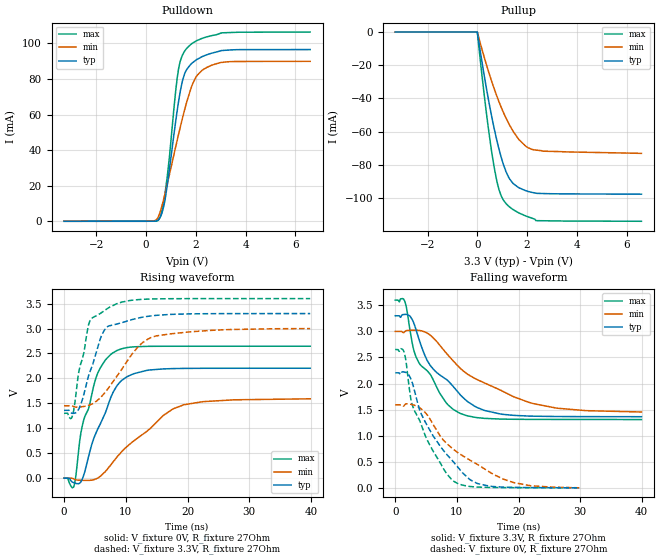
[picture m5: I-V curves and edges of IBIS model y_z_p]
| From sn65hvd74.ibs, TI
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|   y_z Model
[Model]   y_z_p
Model_type   Output
Polarity   Non-Inverting
Vmeas = 1.65
Vref = 1.956
Cref = 50pF
Rref = 27
|   typ   min   max
|   (nom PVT)   (fast PVT)   (slow PVT)
|Avergae
C_comp   1.391e-11   1.371e-11   1.548e-11
| Where nom  PVT is Nominal Process, 3.3V, 27C
|   Fast PVT is Strong Process,  3.6V, -40C
|   Slow PVT is Weak Process,   3V, 150C
[Voltage Range]   3.3   3   3.6
|Junction Temperature
[Temperature Range]   27   150   -40
[Pullup Reference]   3.3   3   3.6
[Pulldown Reference]   0   0   0
[Power Clamp Reference]   3.3   3   3.6
[GND Clamp Reference]   0   0   0
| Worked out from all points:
|   slope of the pulldown table from 0 to 0.495 V, typ, clamps not added: 584 ohm
|   slope of the pullup table from 0 to 0.495 V, typ, clamps not added: 11.1 ohm
|   falling waveform, V_fixture 3.3V, R_fixture 27Ohm: 20-80 % time 7.14ns typ, 11.4ns min, 5.25ns max; typ from 3.3 V to 1.36 V
|   rising waveform, V_fixture 0V, R_fixture 27Ohm: 20-80 % time 4.15ns typ, 8.36ns min, 3.15ns max; typ from 0 V to 2.2 V
|   rising waveform, V_fixture 3.3V, R_fixture 27Ohm: 20-80 % time 2.94ns typ, 5.55ns min, 2.14ns max; typ from 1.36 V to 3.3 V
|   falling waveform, V_fixture 0V, R_fixture 27Ohm: 20-80 % time 6.51ns typ, 9.22ns min, 4.98ns max; typ from 2.21 V to 0 V
[Pulldown]
|   Voltage   I(typ)   I(min)   I(max)
-3.3V     -6.612uA   -9.318uA   -6.374uA
336mV     41.43uA    229.2uA    18.75uA
519.6mV   1.175mA    3.381mA    1.076mA
670.8mV   6.19mA     10.37mA    7.974mA
847.2mV   19.71mA    20.58mA    24.58mA
1.207V    57.83mA    42.86mA    75.34mA
1.311V    67.7mA     49.13mA    85.95mA
1.541V    82.6mA     62.22mA    95.46mA
1.815V    88.49mA    75.13mA    99.61mA
2.253V    92.56mA    84.88mA    102.8mA
3.021V    95.98mA    89.33mA    105.9mA
6.6V      96.55mA    89.94mA    106.4mA
[Pullup]
|   Voltage   I(typ)   I(min)   I(max)
-3.3V     13.22uA    17.2uA     13.33uA
0V        0A         0A         0A
372mV     -34.39mA   -19.93mA   -49.55mA
672mV     -57.7mA    -33.86mA   -80.94mA
816mV     -67.2mA    -39.81mA   -91.73mA
955.2mV   -75.16mA   -45.09mA   -98.48mA
1.155V    -84.1mA    -51.84mA   -103.3mA
1.296V    -88.39mA   -56mA      -105.3mA
1.68V     -93.83mA   -64.82mA   -109mA
2.212V    -96.61mA   -70.72mA   -112.2mA
2.358V    -97mA      -71.09mA   -113.6mA
6.6V      -97.65mA   -73.05mA   -114mA
[Ramp]
R_load = 27
|   typ   min   max
dV/dt_r   1.3224/4.12948e-09   0.954711/8.31809e-09   1.58721/3.15212e-09
dV/dt_f   1.16141/7.1332e-09   0.927257/1.13811e-08   1.37377/5.21426e-09
[Falling Waveform]
V_fixture = 3.3V
V_fixture_min = 3V
V_fixture_max = 3.6V
R_fixture = 27Ohm
|   Time   V(typ)   V(min)   V(max)
0s        3.3V       3V         3.6V
1.55ns    3.325V     2.998V     3.576V
2.89ns    3.194V     3.023V     2.695V
3.83ns    2.857V     3.019V     2.402V
5.645ns   2.353V     2.931V     2.182V
8.245ns   2.082V     2.589V     1.635V
10.37ns   1.809V     2.312V     1.438V
14.48ns   1.484V     2.012V     1.333V
22.48ns   1.374V     1.613V     1.313V
39.95ns   1.364V     1.454V     1.31V
[Rising Waveform]
V_fixture = 0V
V_fixture_min = 0V
V_fixture_max = 0V
R_fixture = 27Ohm
|   Time   V(typ)   V(min)   V(max)
0s        11.3nV     106.8nV    12.29nV
1.57ns    -90.21mV   -13.88mV   -175.1mV
1.945ns   -105mV     -33.14mV   75.73mV
2.735ns   -72.71mV   -41.79mV   907.2mV
5.445ns   981.1mV    1.497mV    2.102V
6.75ns    1.329V     141mV      2.378V
8.525ns   1.846V     417.5mV    2.557V
11.37ns   2.097V     754.6mV    2.634V
19.39ns   2.201V     1.472V     2.645V
39.85ns   2.204V     1.591V     2.645V
[Rising Waveform]
V_fixture = 3.3V
V_fixture_min = 3V
V_fixture_max = 3.6V
R_fixture = 27Ohm
|   Time   V(typ)   V(min)   V(max)
0s        1.36V      1.452V     1.301V
1.395ns   1.3V       1.446V     1.26V
2.635ns   1.452V     1.429V     2.266V
3.185ns   1.669V     1.437V     2.498V
4.175ns   2.127V     1.468V     3.149V
6.555ns   2.972V     1.706V     3.36V
8.56ns    3.09V      2.043V     3.498V
11.89ns   3.207V     2.618V     3.578V
14.92ns   3.264V     2.852V     3.595V
39.85ns   3.3V       3V         3.6V
[Falling Waveform]
V_fixture = 0V
V_fixture_min = 0V
V_fixture_max = 0V
R_fixture = 27Ohm
|   Time   V(typ)   V(min)   V(max)
0s        2.206V     1.592V     2.652V
1.365ns   2.223V     1.569V     2.624V
2.215ns   2.16V      1.609V     1.967V
2.695ns   2.041V     1.598V     1.616V
5.2ns     1.192V     1.398V     913.7mV
9.46ns    495.8mV    735.9mV    127.8mV
12.23ns   150.3mV    525.1mV    24.73mV
15.38ns   30.72mV    297.4mV    7.547mV
21.96ns   4.958mV    40.46mV    2.357mV
29.85ns   493.2uV    901.7uV    380.4uV
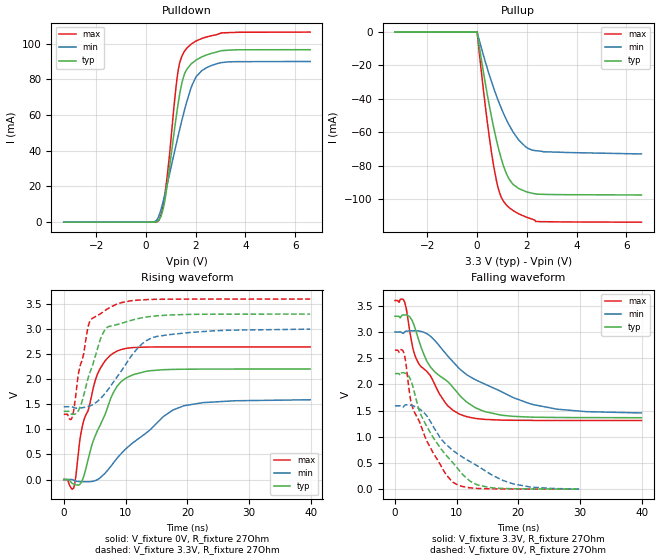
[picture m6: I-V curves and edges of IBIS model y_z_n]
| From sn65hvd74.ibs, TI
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[Model]   y_z_n
Model_type   Output
Polarity   Non-Inverting
Vmeas = 1.65
Vref = 1.956
Cref = 50pF
Rref = 27
|   typ   min   max
|   (nom PVT)   (fast PVT)   (slow PVT)
|Avergae
C_comp   1.391e-11   1.371e-11   1.548e-11
| Where nom  PVT is Nominal Process, 3.3V, 27C
|   Fast PVT is Strong Process,  3.6V, -40C
|   Slow PVT is Weak Process,   3V, 150C
[Voltage Range]   3.3   3   3.6
|Junction Temperature
[Temperature Range]   27   150   -40
[Pullup Reference]   3.3   3   3.6
[Pulldown Reference]   0   0   0
[Power Clamp Reference]   3.3   3   3.6
[GND Clamp Reference]   0   0   0
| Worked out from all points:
|   slope of the pulldown table from 0 to 0.495 V, typ, clamps not added: 584 ohm
|   slope of the pullup table from 0 to 0.495 V, typ, clamps not added: 11.1 ohm
|   falling waveform, V_fixture 3.3V, R_fixture 27Ohm: 20-80 % time 7.14ns typ, 11.4ns min, 5.25ns max; typ from 3.3 V to 1.36 V
|   rising waveform, V_fixture 0V, R_fixture 27Ohm: 20-80 % time 4.14ns typ, 8.35ns min, 3.14ns max; typ from 0 V to 2.2 V
|   rising waveform, V_fixture 3.3V, R_fixture 27Ohm: 20-80 % time 2.95ns typ, 5.55ns min, 2.15ns max; typ from 1.36 V to 3.3 V
|   falling waveform, V_fixture 0V, R_fixture 27Ohm: 20-80 % time 6.51ns typ, 9.22ns min, 4.99ns max; typ from 2.21 V to 0 V
[Pulldown]
|   Voltage   I(typ)   I(min)   I(max)
-3.3V     -6.612uA   -9.318uA   -6.374uA
336mV     41.43uA    229.2uA    18.75uA
519.6mV   1.175mA    3.381mA    1.076mA
670.8mV   6.19mA     10.37mA    7.974mA
847.2mV   19.71mA    20.58mA    24.58mA
1.207V    57.83mA    42.86mA    75.34mA
1.311V    67.7mA     49.13mA    85.95mA
1.541V    82.6mA     62.22mA    95.46mA
1.815V    88.49mA    75.13mA    99.61mA
2.253V    92.56mA    84.88mA    102.8mA
3.021V    95.98mA    89.33mA    105.9mA
6.6V      96.55mA    89.94mA    106.4mA
[Pullup]
|   Voltage   I(typ)   I(min)   I(max)
-3.3V     13.22uA    17.2uA     13.33uA
0V        0A         0A         0A
372mV     -34.39mA   -19.93mA   -49.55mA
672mV     -57.7mA    -33.86mA   -80.94mA
816mV     -67.2mA    -39.81mA   -91.73mA
955.2mV   -75.16mA   -45.09mA   -98.48mA
1.155V    -84.1mA    -51.84mA   -103.3mA
1.296V    -88.39mA   -56mA      -105.3mA
1.68V     -93.83mA   -64.82mA   -109mA
2.212V    -96.61mA   -70.72mA   -112.2mA
2.358V    -97mA      -71.09mA   -113.6mA
6.6V      -97.65mA   -73.05mA   -114mA
[Ramp]
R_load = 27
|   typ   min   max
dV/dt_r   1.32241/4.11811e-09   0.954711/8.31808e-09   1.58722/3.13788e-09
dV/dt_f   1.16141/7.13421e-09   0.927261/1.13804e-08   1.37378/5.21645e-09
[Falling Waveform]
V_fixture = 3.3V
V_fixture_min = 3V
V_fixture_max = 3.6V
R_fixture = 27Ohm
|   Time   V(typ)   V(min)   V(max)
0s        3.3V       3V         3.6V
1.545ns   3.325V     3V         3.576V
2.89ns    3.19V      3.023V     2.695V
3.82ns    2.857V     3.019V     2.403V
5.645ns   2.351V     2.929V     2.182V
8.245ns   2.081V     2.585V     1.635V
10.37ns   1.808V     2.309V     1.438V
14.47ns   1.484V     2.011V     1.333V
22.46ns   1.374V     1.613V     1.313V
39.95ns   1.364V     1.454V     1.31V
[Rising Waveform]
V_fixture = 0V
V_fixture_min = 0V
V_fixture_max = 0V
R_fixture = 27Ohm
|   Time   V(typ)   V(min)   V(max)
0s        11.3nV     106.8nV    12.29nV
1.59ns    -89.85mV   -10.67mV   -175.7mV
1.965ns   -104.7mV   -32.07mV   74.11mV
2.76ns    -74.24mV   -41.8mV    906.7mV
5.455ns   974.5mV    -1.406mV   2.102V
6.795ns   1.332V     139.6mV    2.384V
8.615ns   1.858V     422.4mV    2.562V
11.38ns   2.097V     750.4mV    2.634V
19.43ns   2.201V     1.471V     2.645V
39.85ns   2.204V     1.591V     2.645V
[Rising Waveform]
V_fixture = 3.3V
V_fixture_min = 3V
V_fixture_max = 3.6V
R_fixture = 27Ohm
|   Time   V(typ)   V(min)   V(max)
0s        1.36V      1.452V     1.301V
1.41ns    1.3V       1.448V     1.259V
2.655ns   1.449V     1.428V     2.268V
3.185ns   1.656V     1.436V     2.484V
4.195ns   2.124V     1.467V     3.148V
6.595ns   2.974V     1.704V     3.363V
8.56ns    3.089V     2.035V     3.498V
11.96ns   3.209V     2.621V     3.579V
14.96ns   3.265V     2.852V     3.595V
39.85ns   3.3V       3V         3.6V
[Falling Waveform]
V_fixture = 0V
V_fixture_min = 0V
V_fixture_max = 0V
R_fixture = 27Ohm
|   Time   V(typ)   V(min)   V(max)
0s        2.206V     1.592V     2.652V
1.405ns   2.221V     1.575V     2.611V
2.22ns    2.158V     1.608V     1.959V
2.83ns    1.988V     1.593V     1.566V
5.19ns    1.192V     1.395V     916.1mV
9.435ns   497.7mV    735.5mV    129.9mV
12.23ns   149.5mV    523mV      24.73mV
15.38ns   30.65mV    295.4mV    7.558mV
21.94ns   4.967mV    40.32mV    2.364mV
29.85ns   490.4uV    899.9uV    338.3uV
